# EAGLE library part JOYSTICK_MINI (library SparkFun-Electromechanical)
Small 5-way tactile joystick, COM-10063 4UCON SF303GJ26

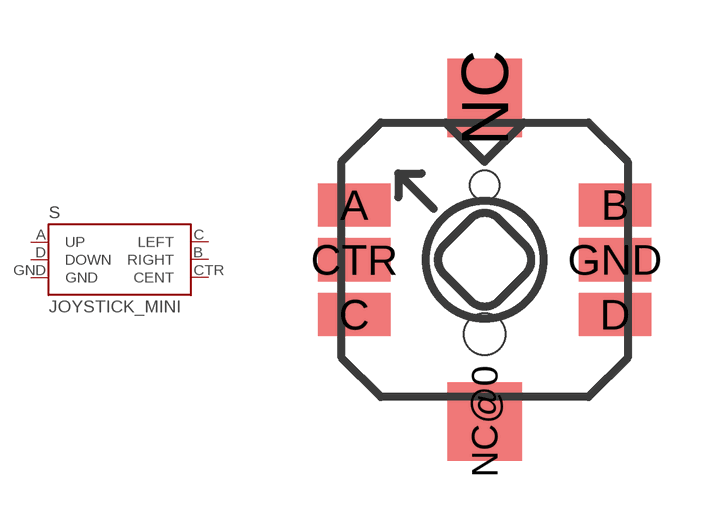
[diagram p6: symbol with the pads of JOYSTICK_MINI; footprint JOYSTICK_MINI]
Designator prefix S

## JOYSTICK_MINI (PROD_ID: SWCH-09905)  [JOYSTICK_MINI]
A  UP
B  RIGHT
C  LEFT
CTR  CENT
D  DOWN
GND  GND

## Footprint JOYSTICK_MINI (pad centres in mm)
smd 1.85 x 1.1: A -3.325,1.4; B 3.325,1.4; C -3.325,-1.4; CTR -3.325,0; D 3.325,-1.4; GND 3.325,0
smd 1.9 x 2: NC 0,4.13; NC@0 0,-4.13
hole 0.75 at 0,1.9
hole 1.05 at 0,-1.9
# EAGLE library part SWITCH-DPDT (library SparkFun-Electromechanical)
DPDT Version of the COM-00597

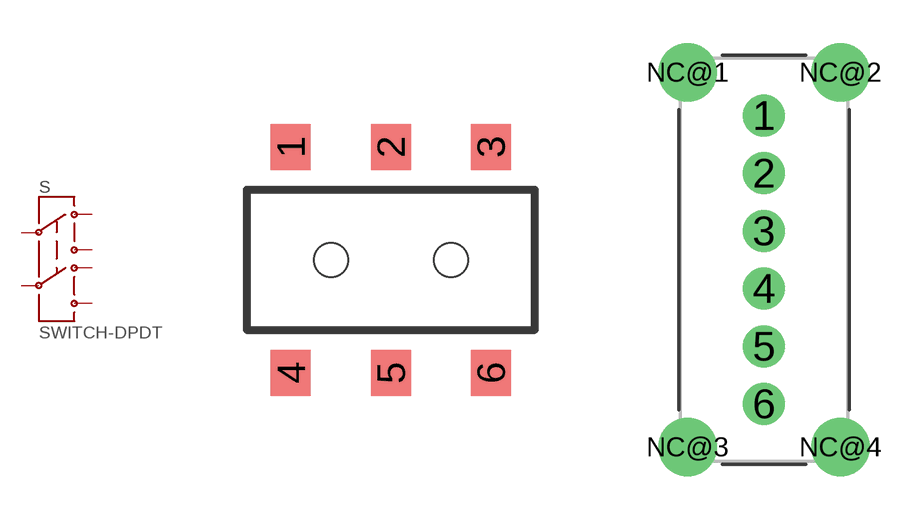
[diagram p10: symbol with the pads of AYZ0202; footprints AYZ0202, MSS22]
Designator prefix S

## SWITCH-DPDTAYZ0202 (PROD_ID: SWCH-08179; VALUE: DPDT)  [AYZ0202]
1  1
2  2
3  3
4  4
5  5
6  6

## SWITCH-DPDTPTH  [MSS22]
Pads as for AYZ0202

## SWITCH-DPDTPTH1  [MS]
Pads as for AYZ0202

## SWITCH-DPDTES  [ES]
Pads as for AYZ0202

## SWITCH-DPDTOS  [OS]
Pads as for AYZ0202

## SWITCH-DPDTEG2211  [EG2211]
P1  2
P1-TA  1
P1-TB  3
P2  5
P2-TA  4
P2-TB  6

## SWITCH-DPDTGPI  [GPI-152-3013]
10  1
11  4
20  3
21  6
C@1  2
C@2  5

## SWITCH-DPDTSTOMP-PTH  [STOMP-SWITCH-DPDT]
P$1  1
P$2  2
P$3  3
P$4  4
P$5  5
P$6  6

## Footprint AYZ0202 (pad centres in mm)
DPDT Slide Switch SMD www.SparkFun.com SKU : Comp-SMDS
smd 1 x 1.15: 1 -2.5,2.825; 2 0,2.825; 3 2.5,2.825; 4 -2.5,-2.825; 5 0,-2.825; 6 2.5,-2.825
hole 0.85 at 1.5,0
hole 0.85 at -1.5,0

## Footprint MSS22 (pad centres in mm)
MSS22 DPDT Switch
drill 0.95: 1 2.65,11.5; 2 2.65,9.5; 3 2.65,7.5; 4 2.65,5.5; 5 2.65,3.5; 6 2.65,1.5
drill 1.35: NC@1 0,13; NC@2 5.3,13; NC@3 0,0; NC@4 5.3,0

## Footprint MS (pad centres in mm)
Series S Slide Switch
drill 2.8 pad 3.302: 1 -3.81,-6.35; 2 -3.81,0; 3 -3.81,6.35; 4 3.81,-6.35; 5 3.81,0; 6 3.81,6.35

## Footprint ES (pad centres in mm)
Right Angle Slide Switch. Works with part#ES21MABE
drill 0.864 pad 1.27: 1 2.54,2.54; 2 0,2.54; 3 -2.54,2.54; 4 2.54,0; 5 0,0; 6 -2.54,0
drill 0.9 pad 1.676: NC@1 -2.54,7.62; NC@2 2.54,7.62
